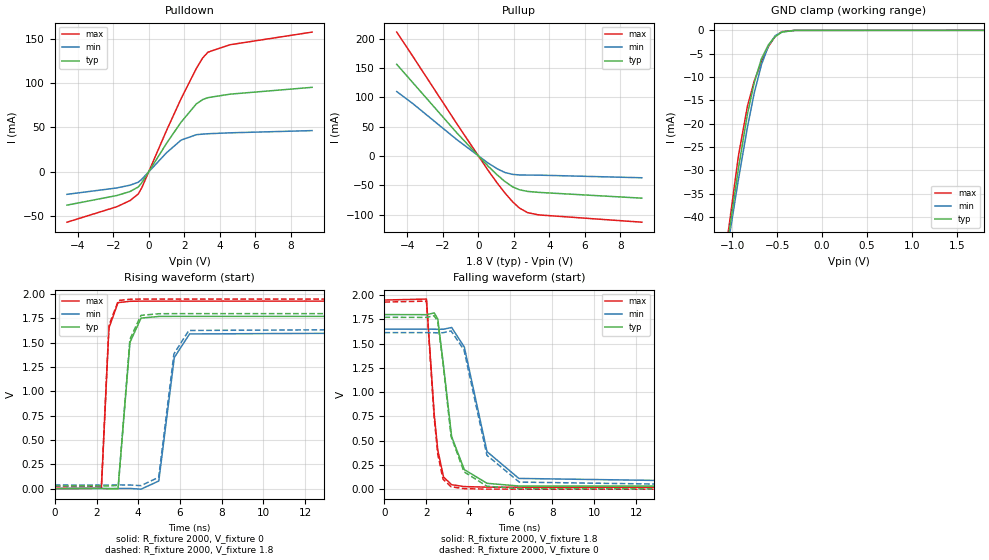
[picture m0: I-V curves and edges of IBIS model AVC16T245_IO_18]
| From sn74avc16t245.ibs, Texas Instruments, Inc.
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[Model]   AVC16T245_IO_18
Model_type  I/O
Vinl=0.5775
Vinh=1.2675
Enable   Active-Low
Vref =   0
Rref =   2000
Cref =   15p
Vmeas =   0.9
| variable   typ   min   max
C_comp   5.11pF   4.44pF   5.78pF
| C_pullup   4.65pF   3.47pF   6.78pF
| C_pulldown   4.54pF   4.02pF   4.93pF
| C_tri-state   5.11pF   4.44pF   5.78pF
[Temperature Range]   40   100   -40
| Ambient temperature   25   85   -40
[Voltage range]   1.8   1.65   1.95
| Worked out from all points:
|   slope of the pulldown table from 0 to 0.27 V, typ, clamps not added: 30.8 ohm
|   slope of the pullup table from 0 to 0.27 V, typ, clamps not added: 31.4 ohm
|   GND clamp passes 1 mA (typ) near -0.50 V on its own axis
|   rising waveform, R_fixture 2000, V_fixture 0: 20-80 % time 304ps typ, 477ps min, 200ps max; typ from 0 V to 1.77 V
|   falling waveform, R_fixture 2000, V_fixture 1.8: 20-80 % time 644ps typ, 985ps min, 377ps max; typ from 1.8 V to 0.027 V
|   rising waveform, R_fixture 2000, V_fixture 1.8: 20-80 % time 302ps typ, 468ps min, 199ps max; typ from 0.027 V to 1.8 V
|   falling waveform, R_fixture 2000, V_fixture 0: 20-80 % time 647ps typ, 985ps min, 363ps max; typ from 1.77 V to 0 V
[GND Clamp]
| AVC16T245_IO_18
|   Voltage   I(typ)   I(min)   I(max)
-4.6V     -597.8mA   -546.6mA   -662.5mA
-1.1V     -52.11mA   -52.52mA   -51.59mA
-1.075V   -48.66mA   -49.4mA    -47.7mA
-930mV    -29.5mA    -31.88mA   -26.82mA
-830mV    -17.94mA   -20.74mA   -16.24mA
-755mV    -11.24mA   -13.46mA   -10.89mA
-675mV    -6.119mA   -7.407mA   -6.788mA
-595mV    -3.054mA   -3.247mA   -3.436mA
-520mV    -1.318mA   -1.132mA   -1.268mA
-445mV    -373.4uA   -312uA     -266.4uA
-300mV    -9.535uA   -12.09uA   -2.471uA
1.8V      910.1pA    144.8nA    97.77pA
[Pulldown]
| AVC16T245_IO_18
|   Voltage   I(typ)   I(min)   I(max)
-4.6V     -37.94mA   -25.73mA   -57.23mA
-1.805V   -27.11mA   -18.54mA   -39.83mA
-1.045V   -22.5mA    -15.36mA   -32.7mA
-590mV    -17.44mA   -12.06mA   -25.35mA
-395mV    -12.81mA   -8.801mA   -18.52mA
1.005V    31.93mA    21.31mA    46.48mA
1.825V    55.97mA    35.61mA    82.46mA
2.68V     76.51mA    41.68mA    116.5mA
3.045V    81.48mA    42.38mA    128.6mA
3.34V     83.6mA     42.77mA    135mA
4.58V     87.53mA    43.81mA    143.4mA
9.2V      95.24mA    46.32mA    157.7mA
[Pullup]
| AVC16T245_IO_18
|   Voltage   I(typ)   I(min)   I(max)
-4.6V     156.3mA    109.9mA    211.2mA
-3.695V   125.1mA    89.45mA    169.9mA
-1.245V   40.55mA    28.8mA     56.51mA
535mV     -16.77mA   -11.6mA    -23.84mA
1.065V    -32.16mA   -21.66mA   -46.14mA
1.49V     -43.16mA   -27.88mA   -62.67mA
1.925V    -52.28mA   -31.05mA   -77.72mA
2.305V    -57.27mA   -32.09mA   -88.3mA
2.77V     -60.1mA    -32.26mA   -96.25mA
3.4V      -61.74mA   -32.39mA   -100.1mA
9.2V      -71.58mA   -36.85mA   -112.5mA
[Ramp]
| AVC16T245_IO_18
| variable   typ   min   max
dV/dt_r   1.08/3.09E-10   0.98/4.91E-10   1.17/2.09E-10
dV/dt_f   1.08/6.50E-10   0.98/9.91E-10   1.17/3.80E-10
R_load = 2000
[Rising Waveform]
| AVC16T245_IO_18
R_fixture =   2000
C_fixture =   0
L_fixture =   0
V_fixture =   0
V_fixture_min = 0
V_fixture_max = 0
|   Time   V(typ)   V(min)   V(max)
0s        21.36nV    98.35nV    643.8pV
2.235ns   949.4uV    -63.59uV   3.922mV
2.595ns   -1.239mV   -113.9uV   1.653V
3.03ns    -3.68mV    864.5uV    1.913V
3.605ns   1.506V     863.1uV    1.927V
4.135ns   1.754V     -6.252mV   1.929V
4.985ns   1.771V     77.87mV    1.929V
5.73ns    1.772V     1.349V     1.929V
6.46ns    1.772V     1.591V     1.929V
29.99ns   1.772V     1.614V     1.929V
[Falling Waveform]
| AVC16T245_IO_18
R_fixture =   2000
C_fixture =   0
L_fixture =   0
V_fixture =   1.8
V_fixture_min = 1.65
V_fixture_max = 1.95
|   Time   V(typ)   V(min)   V(max)
0s        1.8V       1.65V      1.95V
2ns       1.799V     1.65V      1.96V
2.37ns    1.817V     1.649V     772.9mV
2.54ns    1.756V     1.648V     404.3mV
2.815ns   1.272V     1.649V     125.7mV
3.2ns     542.3mV    1.667V     45.87mV
3.805ns   201.5mV    1.466V     26.6mV
4.89ns    60.27mV    386.5mV    20.79mV
6.405ns   32.62mV    110.7mV    20.48mV
29.99ns   27.15mV    36.21mV    20.45mV
[Rising Waveform]
| AVC16T245_IO_18
R_fixture =   2000
C_fixture =   0
L_fixture =   0
V_fixture =   1.8
V_fixture_min = 1.65
V_fixture_max = 1.95
|   Time   V(typ)   V(min)   V(max)
0s        27.15mV    36.2mV     20.45mV
2.235ns   28.1mV     36.15mV    24.76mV
2.595ns   25.84mV    36.11mV    1.678V
3.05ns    33.75mV    37.12mV    1.935V
3.6ns     1.536V     36.95mV    1.948V
4.13ns    1.782V     29.99mV    1.95V
4.98ns    1.799V     116.3mV    1.95V
5.71ns    1.8V       1.386V     1.95V
6.425ns   1.8V       1.627V     1.95V
29.99ns   1.8V       1.65V      1.95V
[Falling Waveform]
| AVC16T245_IO_18
R_fixture =   2000
C_fixture =   0
L_fixture =   0
V_fixture =   0
V_fixture_min = 0
V_fixture_max = 0
|   Time   V(typ)   V(min)   V(max)
0s        1.772V     1.614V     1.929V
2ns       1.771V     1.614V     1.939V
2.37ns    1.789V     1.613V     737.3mV
2.54ns    1.728V     1.612V     361mV
2.79ns    1.298V     1.613V     102.7mV
3.175ns   543.2mV    1.631V     24.59mV
3.79ns    179.1mV    1.436V     5.496mV
4.88ns    30.63mV    350.1mV    297.6uV
6.425ns   4.753mV    72.69mV    23.38uV
29.99ns   49.09nV    1.181uV    138.4nV
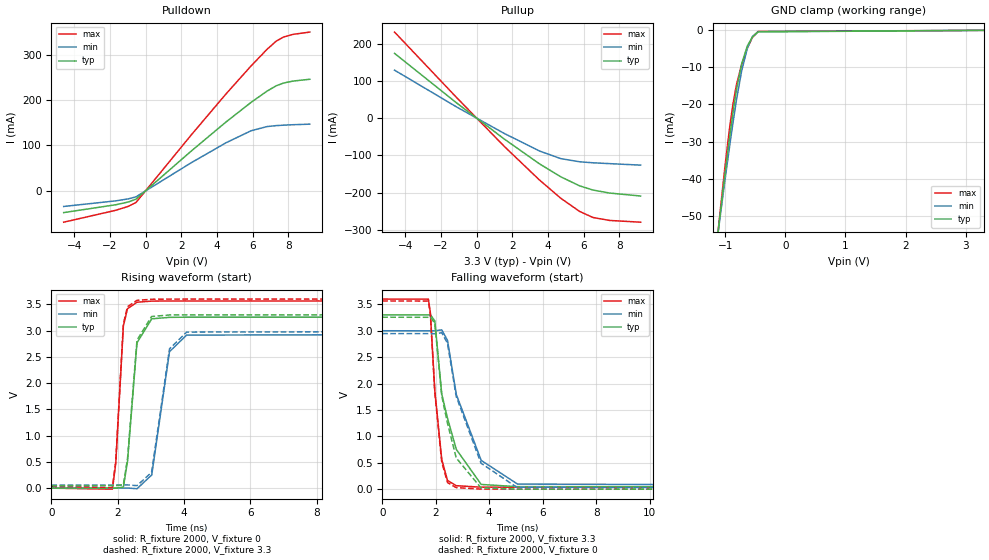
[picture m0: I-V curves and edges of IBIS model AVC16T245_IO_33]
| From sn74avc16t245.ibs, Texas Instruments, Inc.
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[Model]   AVC16T245_IO_33
Model_type  I/O
Vinl=0.8
Vinh=2.0
Enable   Active-Low
Vref =   0
Rref =   2000
Cref =   15p
Vmeas =   1.65
| variable   typ   min   max
C_comp   4.80pF   4.02pF   5.70pF
| C_pullup   3.86pF   2.95pF   5.16pF
| C_pulldown   4.06pF   3.58pF   4.65pF
| C_tri-state   4.80pF   4.02pF   5.70pF
[Temperature Range]   40   100   -40
| Ambient temperature   25   85   -40
[Voltage range]   3.3   3   3.6
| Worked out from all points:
|   slope of the pulldown table from 0 to 0.495 V, typ, clamps not added: 28.7 ohm
|   slope of the pullup table from 0 to 0.495 V, typ, clamps not added: 27.4 ohm
|   GND clamp passes 1 mA (typ) near -0.50 V on its own axis
|   rising waveform, R_fixture 2000, V_fixture 0: 20-80 % time 230ps typ, 350ps min, 168ps max; typ from 0 V to 3.26 V
|   falling waveform, R_fixture 2000, V_fixture 3.3: 20-80 % time 746ps typ, 999ps min, 330ps max; typ from 3.3 V to 0.046 V
|   rising waveform, R_fixture 2000, V_fixture 3.3: 20-80 % time 229ps typ, 351ps min, 168ps max; typ from 0.046 V to 3.3 V
|   falling waveform, R_fixture 2000, V_fixture 0: 20-80 % time 662ps typ, 999ps min, 325ps max; typ from 3.26 V to 0 V
[GND Clamp]
| AVC16T245_IO_33
|   Voltage   I(typ)   I(min)   I(max)
-4.6V     -597.8mA   -546.6mA   -662.5mA
-1.12V    -54.88mA   -55.04mA   -54.73mA
-1.09V    -50.72mA   -51.27mA   -50.03mA
-1V       -38.53mA   -40.19mA   -36.43mA
-920mV    -28.25mA   -30.71mA   -25.57mA
-870mV    -22.29mA   -25.06mA   -19.99mA
-810mV    -15.96mA   -18.69mA   -14.59mA
-725mV    -9.083mA   -10.96mA   -9.257mA
-630mV    -4.179mA   -4.838mA   -4.797mA
-545mV    -1.809mA   -1.649mA   -1.862mA
-450mV    -412.7uA   -343uA     -301.7uA
3.3V      1.631nA    2.398uA    228.2pA
[Pulldown]
| AVC16T245_IO_33
|   Voltage   I(typ)   I(min)   I(max)
-4.6V     -47.48mA   -33.99mA   -68.59mA
-1.68V    -30.25mA   -21.7mA    -42.42mA
-975mV    -24.15mA   -17.32mA   -33.81mA
-545mV    -17.86mA   -12.84mA   -25.24mA
2.54V     87.35mA    61.85mA    122.6mA
4.5V      151.6mA    105.9mA    213.3mA
5.905V    194.7mA    132.4mA    274.8mA
6.805V    219.6mA    141.6mA    311.5mA
7.315V    231.2mA    143.7mA    329.3mA
7.73V     237.3mA    144.7mA    338.5mA
8.275V    241.7mA    145.7mA    344.4mA
9.2V      245.6mA    146.9mA    349.3mA
[Pullup]
| AVC16T245_IO_33
|   Voltage   I(typ)   I(min)   I(max)
-4.6V     174.2mA    129.1mA    231.4mA
-1.105V   40.58mA    29.86mA    54.82mA
1.58V     -56.83mA   -41.58mA   -76.89mA
3.53V     -122.6mA   -88.07mA   -166.1mA
4.725V    -157.4mA   -108.5mA   -215.1mA
5.775V    -181.6mA   -117mA     -250.3mA
6.525V    -192.9mA   -119.7mA   -266.7mA
7.46V     -201mA     -122mA     -274.6mA
9.2V      -209mA     -126mA     -279.3mA
[Ramp]
| AVC16T245_IO_33
| variable   typ   min   max
dV/dt_r   1.97/2.35E-10   1.79/3.59E-10   2.16/1.73E-10
dV/dt_f   1.95/7.46E-10   1.78/1.00E-09   2.14/3.31E-10
R_load = 2000
[Rising Waveform]
| AVC16T245_IO_33
R_fixture =   2000
C_fixture =   0
L_fixture =   0
V_fixture =   0
V_fixture_min = 0
V_fixture_max = 0
|   Time   V(typ)   V(min)   V(max)
0s        38nV       120.5nV    1.922nV
1.84ns    1.734mV    -32.93uV   -19.31mV
1.94ns    173.4uV    6.665uV    471mV
2.17ns    20.4mV     900.5uV    3.092V
2.295ns   514mV      2.498mV    3.417V
2.58ns    2.768V     -11.07mV   3.54V
3.025ns   3.224V     251.5mV    3.561V
3.56ns    3.252V     2.598V     3.564V
4.075ns   3.255V     2.914V     3.564V
29.99ns   3.256V     2.946V     3.564V
[Falling Waveform]
| AVC16T245_IO_33
R_fixture =   2000
C_fixture =   0
L_fixture =   0
V_fixture =   3.3
V_fixture_min = 3
V_fixture_max = 3.6
|   Time   V(typ)   V(min)   V(max)
0s        3.3V       3V         3.6V
1.725ns   3.299V     2.999V     3.598V
1.8ns     3.302V     2.999V     3.34V
1.965ns   3.188V     2.998V     1.867V
2.225ns   1.803V     3.017V     563.6mV
2.44ns    1.343V     2.817V     165.4mV
2.77ns    752.8mV    1.793V     65.72mV
3.7ns     89.38mV    544.7mV    37.52mV
5.06ns    47.69mV    96.09mV    36.37mV
29.99ns   46.48mV    58.85mV    36.33mV
[Rising Waveform]
| AVC16T245_IO_33
R_fixture =   2000
C_fixture =   0
L_fixture =   0
V_fixture =   3.3
V_fixture_min = 3
V_fixture_max = 3.6
|   Time   V(typ)   V(min)   V(max)
0s        46.48mV    58.85mV    36.33mV
1.835ns   48.09mV    58.82mV    10.09mV
1.94ns    46.63mV    58.86mV    508.1mV
2.17ns    67.09mV    59.76mV    3.131V
2.295ns   562.7mV    61.35mV    3.455V
2.58ns    2.817V     47.62mV    3.576V
3.02ns    3.268V     300.3mV    3.596V
3.56ns    3.297V     2.652V     3.599V
4.08ns    3.299V     2.972V     3.6V
29.99ns   3.3V       3V         3.6V
[Falling Waveform]
| AVC16T245_IO_33
R_fixture =   2000
C_fixture =   0
L_fixture =   0
V_fixture =   0
V_fixture_min = 0
V_fixture_max = 0
|   Time   V(typ)   V(min)   V(max)
0s        3.256V     2.946V     3.564V
1.725ns   3.255V     2.945V     3.562V
1.8ns     3.258V     2.944V     3.305V
1.965ns   3.144V     2.943V     1.838V
2.225ns   1.767V     2.963V     509.6mV
2.44ns    1.246V     2.762V     124.7mV
2.765ns   592.3mV    1.757V     29.18mV
3.69ns    26.01mV    493mV      1.19mV
5.025ns   751.8uV    37.46mV    46.61uV
29.99ns   446.5nV    714.4nV    168.9nV
